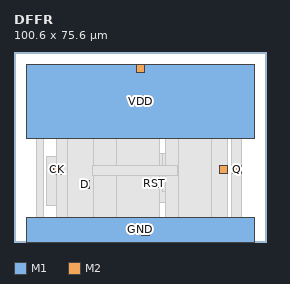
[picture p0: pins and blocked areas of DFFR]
MACRO DFFR
  CLASS CORE ;
  ORIGIN 0 0 ;
  SIZE 100.600 BY 75.600 ;
  SYMMETRY X Y ;
  SITE TR1um_access_site ;
  PIN VDD
    DIRECTION INOUT ;
    USE POWER ;
    PORT
      LAYER M1 ;
        RECT 5.000 41.000 95.600 70.800 ;
      LAYER M2 ;
        RECT 48.600 67.400 52.000 70.800 ;
    END
  END VDD
  PIN GND
    DIRECTION INOUT ;
    USE GROUND ;
    PORT
      LAYER M1 ;
        RECT 5.000 0.000 95.600 9.800 ;
      LAYER M2 ;
        RECT 50.600 2.600 54.000 6.000 ;
    END
  END GND
  PIN CK
    DIRECTION INPUT ;
    USE SIGNAL ;
    PORT
      LAYER M2 ;
        RECT 15.600 27.050 19.000 30.450 ;
    END
  END CK
  PIN D
    DIRECTION INPUT ;
    USE SIGNAL ;
    PORT
      LAYER M2 ;
        RECT 26.500 21.200 29.900 24.600 ;
    END
  END D
  PIN Q
    DIRECTION OUTPUT ;
    USE SIGNAL ;
    PORT
      LAYER M2 ;
        RECT 87.100 27.100 90.500 30.500 ;
    END
  END Q
  PIN QB
    DIRECTION OUTPUT ;
    USE SIGNAL ;
    PORT
      LAYER M2 ;
        RECT 81.600 27.100 85.000 30.500 ;
    END
  END QB
  PIN RST
    DIRECTION INPUT ;
    USE SIGNAL ;
    PORT
      LAYER M2 ;
        RECT 54.100 21.600 57.500 25.000 ;
    END
  END RST
  OBS
    LAYER M1 ;
      RECT 36.700 19.600 39.300 31.200 ;
    LAYER M1 ;
      RECT 13.100 14.350 19.000 34.150 ;
    LAYER M1 ;
      RECT 54.100 15.600 60.300 35.200 ;
    LAYER M1 ;
      RECT 59.100 20.200 65.100 35.200 ;
    LAYER M1 ;
      RECT 26.300 15.200 30.000 35.600 ;
    LAYER M1 ;
      RECT 9.100 6.400 11.700 51.200 ;
    LAYER M1 ;
      RECT 17.100 6.400 24.900 51.200 ;
    LAYER M1 ;
      RECT 21.100 6.400 39.300 51.200 ;
    LAYER M1 ;
      RECT 31.500 6.400 47.300 51.200 ;
    LAYER M1 ;
      RECT 40.700 6.400 57.700 51.200 ;
    LAYER M1 ;
      RECT 60.300 6.400 70.500 51.200 ;
    LAYER M1 ;
      RECT 65.500 6.400 80.600 51.200 ;
    LAYER M1 ;
      RECT 78.700 6.400 85.000 51.200 ;
    LAYER M1 ;
      RECT 86.700 6.400 90.500 51.200 ;
    LAYER V1 ;
      RECT 51.600 3.600 53.000 5.000 ;
    LAYER V1 ;
      RECT 27.500 22.200 28.900 23.600 ;
    LAYER V1 ;
      RECT 55.100 22.600 56.500 24.000 ;
    LAYER V1 ;
      RECT 32.400 27.600 33.800 29.000 ;
    LAYER V1 ;
      RECT 62.700 27.600 64.100 29.000 ;
    LAYER V1 ;
      RECT 16.600 28.050 18.000 29.450 ;
    LAYER V1 ;
      RECT 82.600 28.100 84.000 29.500 ;
    LAYER V1 ;
      RECT 88.100 28.100 89.500 29.500 ;
    LAYER V1 ;
      RECT 49.600 68.400 51.000 69.800 ;
    LAYER M2 ;
      RECT 31.400 26.600 65.100 30.400 ;
  END
END DFFR
